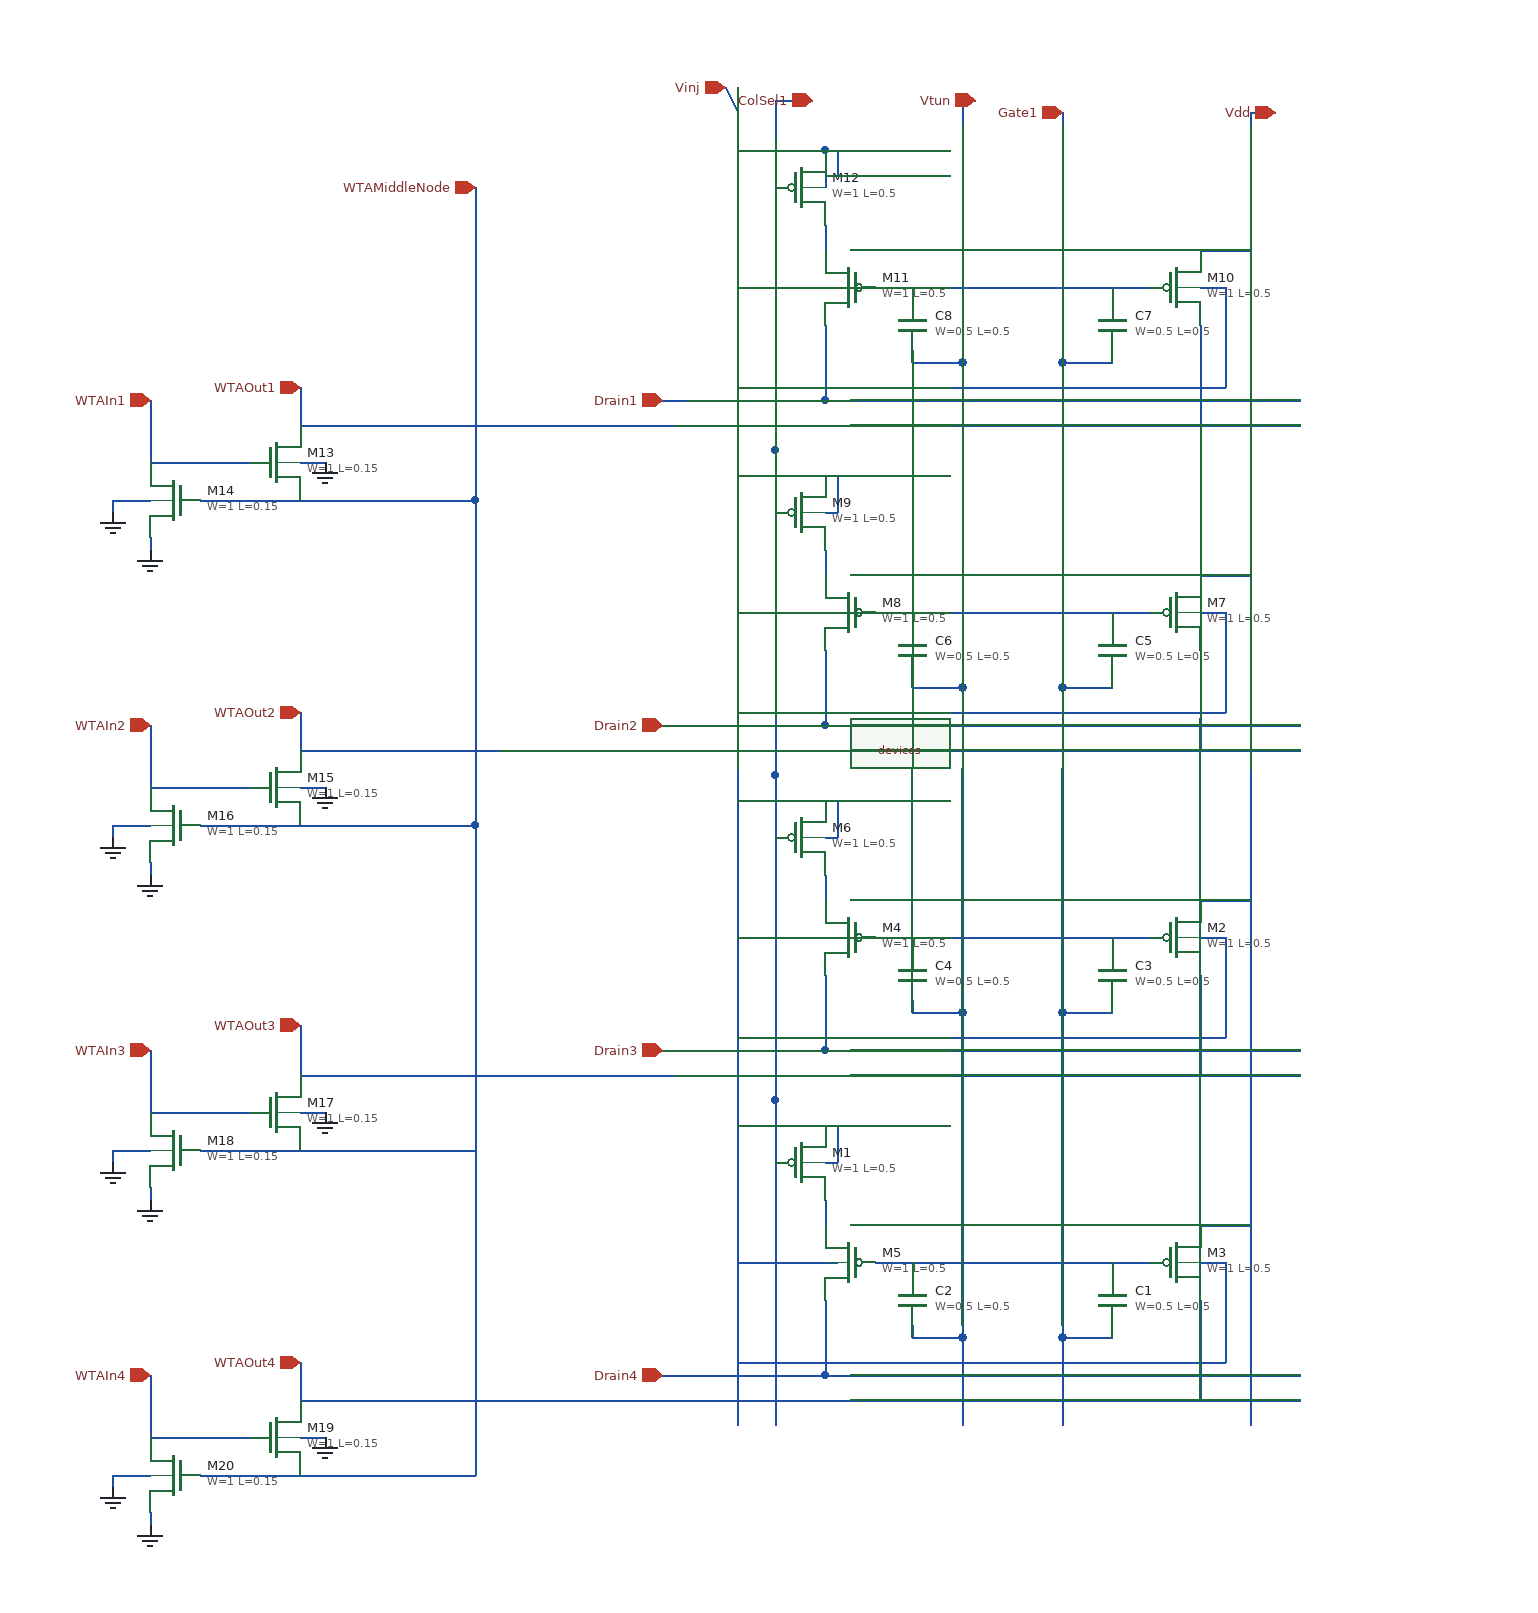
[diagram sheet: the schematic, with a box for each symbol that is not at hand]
v {xschem version=2.9.9 file_version=1.2 }
G {}
K {}
V {}
S {}
E {}
N 790 -910 820 -910 { lab=#net1}
N 750 -860 750 -850 { lab=Gate1}
N 750 -850 790 -850 { lab=Gate1}
N 630 -910 790 -910 { lab=#net1}
N 630 -850 670 -850 { lab=Vtun}
N 630 -860 630 -850 { lab=Vtun}
N 600 -910 630 -910 { lab=#net1}
N 560 -960 560 -940 { lab=#net2}
N 900 -1040 900 -830 { lab=Vdd}
N 440 -800 940 -800 { lab=WTAOut4}
N 900 -830 900 -780 { lab=Vdd}
N 860 -880 860 -800 { lab=WTAOut4}
N 860 -940 900 -940 { lab=Vdd}
N 750 -850 750 -780 { lab=Gate1}
N 750 -1040 750 -850 { lab=Gate1}
N 670 -860 670 -850 { lab=Vtun}
N 670 -850 670 -780 { lab=Vtun}
N 670 -1040 670 -850 { lab=Vtun}
N 520 -1040 520 -990 { lab=ColSel1}
N 520 -1040 520 -780 { lab=ColSel1}
N 560 -880 560 -820 { lab=Drain4}
N 440 -820 560 -820 { lab=Drain4}
N 560 -820 710 -820 { lab=Drain4}
N 710 -820 810 -820 { lab=Drain4}
N 810 -820 880 -820 { lab=Drain4}
N 880 -820 940 -820 { lab=Drain4}
N 490 -1040 490 -780 { lab=Vinj}
N 490 -1020 560 -1020 { lab=Vinj}
N 790 -1170 820 -1170 { lab=#net3}
N 750 -1120 750 -1110 { lab=Gate1}
N 750 -1110 790 -1110 { lab=Gate1}
N 630 -1170 790 -1170 { lab=#net3}
N 630 -1110 670 -1110 { lab=Vtun}
N 630 -1120 630 -1110 { lab=Vtun}
N 600 -1170 630 -1170 { lab=#net3}
N 560 -1220 560 -1200 { lab=#net4}
N 900 -1300 900 -1090 { lab=Vdd}
N 440 -1060 940 -1060 { lab=WTAOut3}
N 900 -1090 900 -1040 { lab=Vdd}
N 860 -1140 860 -1060 { lab=WTAOut3}
N 860 -1200 900 -1200 { lab=Vdd}
N 750 -1110 750 -1040 { lab=Gate1}
N 750 -1300 750 -1110 { lab=Gate1}
N 670 -1120 670 -1110 { lab=Vtun}
N 670 -1110 670 -1040 { lab=Vtun}
N 670 -1300 670 -1110 { lab=Vtun}
N 520 -1300 520 -1250 { lab=ColSel1}
N 520 -1300 520 -1040 { lab=ColSel1}
N 560 -1140 560 -1080 { lab=Drain3}
N 440 -1080 560 -1080 { lab=Drain3}
N 560 -1080 710 -1080 { lab=Drain3}
N 710 -1080 810 -1080 { lab=Drain3}
N 810 -1080 880 -1080 { lab=Drain3}
N 880 -1080 940 -1080 { lab=Drain3}
N 490 -1300 490 -1040 { lab=Vinj}
N 490 -1280 560 -1280 { lab=Vinj}
N 790 -1430 820 -1430 { lab=#net5}
N 750 -1380 750 -1370 { lab=Gate1}
N 750 -1370 790 -1370 { lab=Gate1}
N 630 -1430 790 -1430 { lab=#net5}
N 630 -1370 670 -1370 { lab=Vtun}
N 630 -1380 630 -1370 { lab=Vtun}
N 600 -1430 630 -1430 { lab=#net5}
N 560 -1480 560 -1460 { lab=#net6}
N 900 -1560 900 -1350 { lab=Vdd}
N 440 -1320 940 -1320 { lab=WTAOut2}
N 900 -1350 900 -1300 { lab=Vdd}
N 860 -1400 860 -1320 { lab=WTAOut2}
N 860 -1460 900 -1460 { lab=Vdd}
N 750 -1370 750 -1300 { lab=Gate1}
N 750 -1560 750 -1370 { lab=Gate1}
N 670 -1380 670 -1370 { lab=Vtun}
N 670 -1370 670 -1300 { lab=Vtun}
N 670 -1560 670 -1370 { lab=Vtun}
N 520 -1560 520 -1510 { lab=ColSel1}
N 520 -1560 520 -1300 { lab=ColSel1}
N 560 -1400 560 -1340 { lab=Drain2}
N 440 -1340 560 -1340 { lab=Drain2}
N 560 -1340 710 -1340 { lab=Drain2}
N 710 -1340 810 -1340 { lab=Drain2}
N 810 -1340 880 -1340 { lab=Drain2}
N 880 -1340 940 -1340 { lab=Drain2}
N 490 -1560 490 -1300 { lab=Vinj}
N 490 -1540 560 -1540 { lab=Vinj}
N 790 -1690 820 -1690 { lab=#net7}
N 750 -1640 750 -1630 { lab=Gate1}
N 750 -1630 790 -1630 { lab=Gate1}
N 630 -1690 790 -1690 { lab=#net7}
N 630 -1630 670 -1630 { lab=Vtun}
N 630 -1640 630 -1630 { lab=Vtun}
N 600 -1690 630 -1690 { lab=#net7}
N 560 -1740 560 -1720 { lab=#net8}
N 900 -1820 900 -1610 { lab=Vdd}
N 440 -1580 940 -1580 { lab=WTAOut1}
N 900 -1610 900 -1560 { lab=Vdd}
N 860 -1660 860 -1580 { lab=WTAOut1}
N 860 -1720 900 -1720 { lab=Vdd}
N 750 -1630 750 -1560 { lab=Gate1}
N 750 -1820 750 -1630 { lab=Gate1}
N 670 -1640 670 -1630 { lab=Vtun}
N 670 -1630 670 -1560 { lab=Vtun}
N 670 -1820 670 -1630 { lab=Vtun}
N 520 -1820 520 -1770 { lab=ColSel1}
N 520 -1820 520 -1560 { lab=ColSel1}
N 560 -1660 560 -1600 { lab=Drain1}
N 440 -1600 560 -1600 { lab=Drain1}
N 560 -1600 710 -1600 { lab=Drain1}
N 710 -1600 810 -1600 { lab=Drain1}
N 810 -1600 880 -1600 { lab=Drain1}
N 880 -1600 940 -1600 { lab=Drain1}
N 490 -1820 490 -1560 { lab=Vinj}
N 490 -1800 560 -1800 { lab=Vinj}
N 420 -1600 440 -1600 { lab=Drain1}
N 420 -1580 450 -1580 { lab=WTAOut1}
N 420 -1340 450 -1340 { lab=Drain2}
N 420 -1320 450 -1320 { lab=WTAOut2}
N 420 -1600 450 -1600 { lab=Drain1}
N 420 -1080 450 -1080 { lab=Drain3}
N 420 -1060 450 -1060 { lab=WTAOut3}
N 420 -820 450 -820 { lab=Drain4}
N 420 -800 450 -800 { lab=WTAOut4}
N 900 -1830 900 -1810 { lab=Vdd}
N 750 -1830 750 -1810 { lab=Gate1}
N 670 -1830 670 -1810 { lab=Vtun}
N 520 -1830 520 -1810 { lab=ColSel1}
N 490 -1850 490 -1820 { lab=Vinj}
N 480 -1850 490 -1830 { lab=Vinj}
N 480 -1850 490 -1830 { lab=Vinj}
N 560 -1800 560 -1770 { lab=Vinj}
N 560 -1780 570 -1780 { lab=Vinj}
N 570 -1800 570 -1780 { lab=Vinj}
N 560 -1800 570 -1800 { lab=Vinj}
N 490 -1690 560 -1690 { lab=Vinj}
N 490 -1430 560 -1430 { lab=Vinj}
N 560 -1510 570 -1510 { lab=Vinj}
N 570 -1540 570 -1510 { lab=Vinj}
N 540 -1540 570 -1540 { lab=Vinj}
N 490 -1170 560 -1170 { lab=Vinj}
N 560 -1250 570 -1250 { lab=Vinj}
N 570 -1280 570 -1250 { lab=Vinj}
N 540 -1280 570 -1280 { lab=Vinj}
N 490 -910 570 -910 { lab=Vinj}
N 560 -990 570 -990 { lab=Vinj}
N 570 -1020 570 -990 { lab=Vinj}
N 540 -1020 570 -1020 { lab=Vinj}
N 490 -830 880 -830 { lab=Vinj}
N 880 -910 880 -830 { lab=Vinj}
N 860 -910 880 -910 { lab=Vinj}
N 860 -1170 880 -1170 { lab=Vinj}
N 880 -1170 880 -1090 { lab=Vinj}
N 490 -1090 880 -1090 { lab=Vinj}
N 860 -1430 880 -1430 { lab=Vinj}
N 880 -1430 880 -1350 { lab=Vinj}
N 490 -1350 880 -1350 { lab=Vinj}
N 860 -1690 880 -1690 { lab=Vinj}
N 880 -1690 880 -1610 { lab=Vinj}
N 490 -1610 880 -1610 { lab=Vinj}
N 520 -1840 520 -1830 { lab=ColSel1}
N 520 -1840 550 -1840 { lab=ColSel1}
N 900 -1830 920 -1830 { lab=Vdd}
N 670 -1840 670 -1830 { lab=Vtun}
N 670 -1840 680 -1840 { lab=Vtun}
N 60 -1520 140 -1520 { lab=WTAMiddleNode}
N 20 -1550 100 -1550 { lab=WTAIn1}
N 20 -1600 20 -1550 { lab=WTAIn1}
N 20 -1490 20 -1480 { lab=GND}
N 140 -1520 240 -1520 { lab=WTAMiddleNode}
N 140 -1550 160 -1550 { lab=GND}
N 140 -1580 310 -1580 { lab=WTAOut1}
N 240 -1520 280 -1520 { lab=WTAMiddleNode}
N 60 -1260 140 -1260 { lab=WTAMiddleNode}
N 20 -1290 100 -1290 { lab=WTAIn2}
N 20 -1340 20 -1290 { lab=WTAIn2}
N 20 -1230 20 -1220 { lab=GND}
N 140 -1260 240 -1260 { lab=WTAMiddleNode}
N 140 -1290 160 -1290 { lab=GND}
N 140 -1320 310 -1320 { lab=WTAOut2}
N 240 -1260 280 -1260 { lab=WTAMiddleNode}
N 60 -1000 140 -1000 { lab=WTAMiddleNode}
N 20 -1030 100 -1030 { lab=WTAIn3}
N 20 -1080 20 -1030 { lab=WTAIn3}
N 20 -970 20 -960 { lab=GND}
N 140 -1000 240 -1000 { lab=WTAMiddleNode}
N 140 -1030 160 -1030 { lab=GND}
N 140 -1060 310 -1060 { lab=WTAOut3}
N 240 -1000 280 -1000 { lab=WTAMiddleNode}
N 60 -740 140 -740 { lab=WTAMiddleNode}
N 20 -770 100 -770 { lab=WTAIn4}
N 20 -820 20 -770 { lab=WTAIn4}
N 20 -710 20 -700 { lab=GND}
N 140 -740 240 -740 { lab=WTAMiddleNode}
N 140 -770 160 -770 { lab=GND}
N 140 -800 310 -800 { lab=WTAOut4}
N 240 -740 280 -740 { lab=WTAMiddleNode}
N 310 -1580 420 -1580 { lab=WTAOut1}
N 140 -1610 140 -1580 { lab=WTAOut1}
N 280 -1770 280 -1520 { lab=WTAMiddleNode}
N 280 -1520 280 -1260 { lab=WTAMiddleNode}
N 300 -1320 420 -1320 { lab=WTAOut2}
N 310 -1060 420 -1060 { lab=WTAOut3}
N 310 -800 420 -800 { lab=WTAOut4}
N 280 -1260 280 -740 { lab=WTAMiddleNode}
N 140 -1350 140 -1320 { lab=WTAOut2}
N 140 -1100 140 -1060 { lab=WTAOut3}
N 140 -830 140 -800 { lab=WTAOut4}
N -10 -740 20 -740 { lab=GND}
N -10 -740 -10 -730 { lab=GND}
N -10 -1000 20 -1000 { lab=GND}
N -10 -1000 -10 -990 { lab=GND}
N -10 -1260 20 -1260 { lab=GND}
N -10 -1260 -10 -1250 { lab=GND}
N -10 -1520 20 -1520 { lab=GND}
N -10 -1520 -10 -1510 { lab=GND}
C {sky130_fd_pr/pfet_g5v0d10v5.sym} 840 -910 0 0 {name=M3
L=0.5
W=1
nf=1
mult=1
ad="'int((nf+1)/2) * W/nf * 0.29'" 
pd="'2*int((nf+1)/2) * (W/nf + 0.29)'"
as="'int((nf+2)/2) * W/nf * 0.29'" 
ps="'2*int((nf+2)/2) * (W/nf + 0.29)'"
nrd="'0.29 / W'" nrs="'0.29 / W'"
sa=0 sb=0 sd=0
model=pfet_g5v0d10v5
spiceprefix=X
}
C {sky130_fd_pr/cap_var_hvt.sym} 790 -880 0 0 {name=C1 model=cap_var_hvt W=0.5 L=0.5 VM=1 spiceprefix=X}
C {sky130_fd_pr/pfet_g5v0d10v5.sym} 580 -910 0 1 {name=M5
L=0.5
W=1
nf=1
mult=1
ad="'int((nf+1)/2) * W/nf * 0.29'" 
pd="'2*int((nf+1)/2) * (W/nf + 0.29)'"
as="'int((nf+2)/2) * W/nf * 0.29'" 
ps="'2*int((nf+2)/2) * (W/nf + 0.29)'"
nrd="'0.29 / W'" nrs="'0.29 / W'"
sa=0 sb=0 sd=0
model=pfet_g5v0d10v5
spiceprefix=X
}
C {sky130_fd_pr/cap_var_hvt.sym} 630 -880 0 1 {name=C2 model=cap_var_hvt W=0.5 L=0.5 VM=1 spiceprefix=X}
C {sky130_fd_pr/pfet_g5v0d10v5.sym} 540 -990 0 0 {name=M1
L=0.5
W=1
nf=1
mult=1
ad="'int((nf+1)/2) * W/nf * 0.29'" 
pd="'2*int((nf+1)/2) * (W/nf + 0.29)'"
as="'int((nf+2)/2) * W/nf * 0.29'" 
ps="'2*int((nf+2)/2) * (W/nf + 0.29)'"
nrd="'0.29 / W'" nrs="'0.29 / W'"
sa=0 sb=0 sd=0
model=pfet_g5v0d10v5
spiceprefix=X
}
C {sky130_fd_pr/pfet_g5v0d10v5.sym} 840 -1170 0 0 {name=M2
L=0.5
W=1
nf=1
mult=1
ad="'int((nf+1)/2) * W/nf * 0.29'" 
pd="'2*int((nf+1)/2) * (W/nf + 0.29)'"
as="'int((nf+2)/2) * W/nf * 0.29'" 
ps="'2*int((nf+2)/2) * (W/nf + 0.29)'"
nrd="'0.29 / W'" nrs="'0.29 / W'"
sa=0 sb=0 sd=0
model=pfet_g5v0d10v5
spiceprefix=X
}
C {sky130_fd_pr/cap_var_hvt.sym} 790 -1140 0 0 {name=C3 model=cap_var_hvt W=0.5 L=0.5 VM=1 spiceprefix=X}
C {sky130_fd_pr/pfet_g5v0d10v5.sym} 580 -1170 0 1 {name=M4
L=0.5
W=1
nf=1
mult=1
ad="'int((nf+1)/2) * W/nf * 0.29'" 
pd="'2*int((nf+1)/2) * (W/nf + 0.29)'"
as="'int((nf+2)/2) * W/nf * 0.29'" 
ps="'2*int((nf+2)/2) * (W/nf + 0.29)'"
nrd="'0.29 / W'" nrs="'0.29 / W'"
sa=0 sb=0 sd=0
model=pfet_g5v0d10v5
spiceprefix=X
}
C {sky130_fd_pr/cap_var_hvt.sym} 630 -1140 0 1 {name=C4 model=cap_var_hvt W=0.5 L=0.5 VM=1 spiceprefix=X}
C {sky130_fd_pr/pfet_g5v0d10v5.sym} 540 -1250 0 0 {name=M6
L=0.5
W=1
nf=1
mult=1
ad="'int((nf+1)/2) * W/nf * 0.29'" 
pd="'2*int((nf+1)/2) * (W/nf + 0.29)'"
as="'int((nf+2)/2) * W/nf * 0.29'" 
ps="'2*int((nf+2)/2) * (W/nf + 0.29)'"
nrd="'0.29 / W'" nrs="'0.29 / W'"
sa=0 sb=0 sd=0
model=pfet_g5v0d10v5
spiceprefix=X
}
C {sky130_fd_pr/pfet_g5v0d10v5.sym} 840 -1430 0 0 {name=M7
L=0.5
W=1
nf=1
mult=1
ad="'int((nf+1)/2) * W/nf * 0.29'" 
pd="'2*int((nf+1)/2) * (W/nf + 0.29)'"
as="'int((nf+2)/2) * W/nf * 0.29'" 
ps="'2*int((nf+2)/2) * (W/nf + 0.29)'"
nrd="'0.29 / W'" nrs="'0.29 / W'"
sa=0 sb=0 sd=0
model=pfet_g5v0d10v5
spiceprefix=X
}
C {sky130_fd_pr/cap_var_hvt.sym} 790 -1400 0 0 {name=C5 model=cap_var_hvt W=0.5 L=0.5 VM=1 spiceprefix=X}
C {sky130_fd_pr/pfet_g5v0d10v5.sym} 580 -1430 0 1 {name=M8
L=0.5
W=1
nf=1
mult=1
ad="'int((nf+1)/2) * W/nf * 0.29'" 
pd="'2*int((nf+1)/2) * (W/nf + 0.29)'"
as="'int((nf+2)/2) * W/nf * 0.29'" 
ps="'2*int((nf+2)/2) * (W/nf + 0.29)'"
nrd="'0.29 / W'" nrs="'0.29 / W'"
sa=0 sb=0 sd=0
model=pfet_g5v0d10v5
spiceprefix=X
}
C {sky130_fd_pr/cap_var_hvt.sym} 630 -1400 0 1 {name=C6 model=cap_var_hvt W=0.5 L=0.5 VM=1 spiceprefix=X}
C {sky130_fd_pr/pfet_g5v0d10v5.sym} 540 -1510 0 0 {name=M9
L=0.5
W=1
nf=1
mult=1
ad="'int((nf+1)/2) * W/nf * 0.29'" 
pd="'2*int((nf+1)/2) * (W/nf + 0.29)'"
as="'int((nf+2)/2) * W/nf * 0.29'" 
ps="'2*int((nf+2)/2) * (W/nf + 0.29)'"
nrd="'0.29 / W'" nrs="'0.29 / W'"
sa=0 sb=0 sd=0
model=pfet_g5v0d10v5
spiceprefix=X
}
C {sky130_fd_pr/pfet_g5v0d10v5.sym} 840 -1690 0 0 {name=M10
L=0.5
W=1
nf=1
mult=1
ad="'int((nf+1)/2) * W/nf * 0.29'" 
pd="'2*int((nf+1)/2) * (W/nf + 0.29)'"
as="'int((nf+2)/2) * W/nf * 0.29'" 
ps="'2*int((nf+2)/2) * (W/nf + 0.29)'"
nrd="'0.29 / W'" nrs="'0.29 / W'"
sa=0 sb=0 sd=0
model=pfet_g5v0d10v5
spiceprefix=X
}
C {sky130_fd_pr/cap_var_hvt.sym} 790 -1660 0 0 {name=C7 model=cap_var_hvt W=0.5 L=0.5 VM=1 spiceprefix=X}
C {sky130_fd_pr/pfet_g5v0d10v5.sym} 580 -1690 0 1 {name=M11
L=0.5
W=1
nf=1
mult=1
ad="'int((nf+1)/2) * W/nf * 0.29'" 
pd="'2*int((nf+1)/2) * (W/nf + 0.29)'"
as="'int((nf+2)/2) * W/nf * 0.29'" 
ps="'2*int((nf+2)/2) * (W/nf + 0.29)'"
nrd="'0.29 / W'" nrs="'0.29 / W'"
sa=0 sb=0 sd=0
model=pfet_g5v0d10v5
spiceprefix=X
}
C {sky130_fd_pr/cap_var_hvt.sym} 630 -1660 0 1 {name=C8 model=cap_var_hvt W=0.5 L=0.5 VM=1 spiceprefix=X}
C {sky130_fd_pr/pfet_g5v0d10v5.sym} 540 -1770 0 0 {name=M12
L=0.5
W=1
nf=1
mult=1
ad="'int((nf+1)/2) * W/nf * 0.29'" 
pd="'2*int((nf+1)/2) * (W/nf + 0.29)'"
as="'int((nf+2)/2) * W/nf * 0.29'" 
ps="'2*int((nf+2)/2) * (W/nf + 0.29)'"
nrd="'0.29 / W'" nrs="'0.29 / W'"
sa=0 sb=0 sd=0
model=pfet_g5v0d10v5
spiceprefix=X
}
C {devices} 980 -1480 0 0 {}
C {devices/ipin.sym} 430 -1600 0 0 {name=Drain1 lab=Drain1}
C {devices/ipin.sym} 20 -1600 0 0 {name=WTAIn1 lab=WTAIn1}
C {devices/ipin.sym} 430 -1340 0 0 {name=Drain2 lab=Drain2}
C {devices/ipin.sym} 430 -1080 0 0 {name=Drain3 lab=Drain3}
C {devices/ipin.sym} 430 -820 0 0 {name=Drain4 lab=Drain4}
C {devices/iopin.sym} 920 -1830 0 0 {name=Vdd lab=Vdd}
C {devices/iopin.sym} 750 -1830 0 0 {name=Gate1 lab=Gate1}
C {devices/iopin.sym} 680 -1840 0 0 {name=Vtun lab=Vtun}
C {devices/iopin.sym} 550 -1840 0 0 {name=ColSel1 lab=ColSel1}
C {devices/iopin.sym} 480 -1850 0 0 {name=Vinj lab=Vinj}
C {sky130_fd_pr/nfet_01v8.sym} 120 -1550 0 0 {name=M13
L=0.15
W=1
nf=1 
mult=1
ad="'int((nf+1)/2) * W/nf * 0.29'" 
pd="'2*int((nf+1)/2) * (W/nf + 0.29)'"
as="'int((nf+2)/2) * W/nf * 0.29'" 
ps="'2*int((nf+2)/2) * (W/nf + 0.29)'"
nrd="'0.29 / W'" nrs="'0.29 / W'"
sa=0 sb=0 sd=0
model=nfet_01v8
spiceprefix=X
}
C {devices/gnd.sym} 160 -1550 0 0 {name=l1 lab=GND}
C {sky130_fd_pr/nfet_01v8.sym} 40 -1520 0 1 {name=M14
L=0.15
W=1
nf=1 
mult=1
ad="'int((nf+1)/2) * W/nf * 0.29'" 
pd="'2*int((nf+1)/2) * (W/nf + 0.29)'"
as="'int((nf+2)/2) * W/nf * 0.29'" 
ps="'2*int((nf+2)/2) * (W/nf + 0.29)'"
nrd="'0.29 / W'" nrs="'0.29 / W'"
sa=0 sb=0 sd=0
model=nfet_01v8
spiceprefix=X
}
C {devices/gnd.sym} 20 -1480 0 0 {name=l2 lab=GND}
C {devices/iopin.sym} 140 -1610 0 0 {name=WTAOut1 lab=WTAOut1}
C {devices/ipin.sym} 20 -1340 0 0 {name=WTAIn2 lab=WTAIn2}
C {sky130_fd_pr/nfet_01v8.sym} 120 -1290 0 0 {name=M15
L=0.15
W=1
nf=1 
mult=1
ad="'int((nf+1)/2) * W/nf * 0.29'" 
pd="'2*int((nf+1)/2) * (W/nf + 0.29)'"
as="'int((nf+2)/2) * W/nf * 0.29'" 
ps="'2*int((nf+2)/2) * (W/nf + 0.29)'"
nrd="'0.29 / W'" nrs="'0.29 / W'"
sa=0 sb=0 sd=0
model=nfet_01v8
spiceprefix=X
}
C {devices/gnd.sym} 160 -1290 0 0 {name=l3 lab=GND}
C {sky130_fd_pr/nfet_01v8.sym} 40 -1260 0 1 {name=M16
L=0.15
W=1
nf=1 
mult=1
ad="'int((nf+1)/2) * W/nf * 0.29'" 
pd="'2*int((nf+1)/2) * (W/nf + 0.29)'"
as="'int((nf+2)/2) * W/nf * 0.29'" 
ps="'2*int((nf+2)/2) * (W/nf + 0.29)'"
nrd="'0.29 / W'" nrs="'0.29 / W'"
sa=0 sb=0 sd=0
model=nfet_01v8
spiceprefix=X
}
C {devices/gnd.sym} 20 -1220 0 0 {name=l4 lab=GND}
C {devices/iopin.sym} 140 -1350 0 0 {name=WTAOut2 lab=WTAOut2}
C {devices/ipin.sym} 20 -1080 0 0 {name=WTAIn3 lab=WTAIn3}
C {sky130_fd_pr/nfet_01v8.sym} 120 -1030 0 0 {name=M17
L=0.15
W=1
nf=1 
mult=1
ad="'int((nf+1)/2) * W/nf * 0.29'" 
pd="'2*int((nf+1)/2) * (W/nf + 0.29)'"
as="'int((nf+2)/2) * W/nf * 0.29'" 
ps="'2*int((nf+2)/2) * (W/nf + 0.29)'"
nrd="'0.29 / W'" nrs="'0.29 / W'"
sa=0 sb=0 sd=0
model=nfet_01v8
spiceprefix=X
}
C {devices/gnd.sym} 160 -1030 0 0 {name=l5 lab=GND}
C {sky130_fd_pr/nfet_01v8.sym} 40 -1000 0 1 {name=M18
L=0.15
W=1
nf=1 
mult=1
ad="'int((nf+1)/2) * W/nf * 0.29'" 
pd="'2*int((nf+1)/2) * (W/nf + 0.29)'"
as="'int((nf+2)/2) * W/nf * 0.29'" 
ps="'2*int((nf+2)/2) * (W/nf + 0.29)'"
nrd="'0.29 / W'" nrs="'0.29 / W'"
sa=0 sb=0 sd=0
model=nfet_01v8
spiceprefix=X
}
C {devices/gnd.sym} 20 -960 0 0 {name=l6 lab=GND}
C {devices/iopin.sym} 140 -1100 0 0 {name=WTAOut3 lab=WTAOut3}
C {devices/ipin.sym} 20 -820 0 0 {name=WTAIn4 lab=WTAIn4}
C {sky130_fd_pr/nfet_01v8.sym} 120 -770 0 0 {name=M19
L=0.15
W=1
nf=1 
mult=1
ad="'int((nf+1)/2) * W/nf * 0.29'" 
pd="'2*int((nf+1)/2) * (W/nf + 0.29)'"
as="'int((nf+2)/2) * W/nf * 0.29'" 
ps="'2*int((nf+2)/2) * (W/nf + 0.29)'"
nrd="'0.29 / W'" nrs="'0.29 / W'"
sa=0 sb=0 sd=0
model=nfet_01v8
spiceprefix=X
}
C {devices/gnd.sym} 160 -770 0 0 {name=l7 lab=GND}
C {sky130_fd_pr/nfet_01v8.sym} 40 -740 0 1 {name=M20
L=0.15
W=1
nf=1 
mult=1
ad="'int((nf+1)/2) * W/nf * 0.29'" 
pd="'2*int((nf+1)/2) * (W/nf + 0.29)'"
as="'int((nf+2)/2) * W/nf * 0.29'" 
ps="'2*int((nf+2)/2) * (W/nf + 0.29)'"
nrd="'0.29 / W'" nrs="'0.29 / W'"
sa=0 sb=0 sd=0
model=nfet_01v8
spiceprefix=X
}
C {devices/gnd.sym} 20 -700 0 0 {name=l8 lab=GND}
C {devices/iopin.sym} 140 -830 0 0 {name=WTAOut4 lab=WTAOut4}
C {devices/iopin.sym} 280 -1770 0 0 {name=WTAMiddleNode lab=WTAMiddleNode}
C {devices/gnd.sym} -10 -1510 0 0 {name=l9 lab=GND}
C {devices/gnd.sym} -10 -1250 0 0 {name=l10 lab=GND}
C {devices/gnd.sym} -10 -990 0 0 {name=l11 lab=GND}
C {devices/gnd.sym} -10 -730 0 0 {name=l12 lab=GND}
